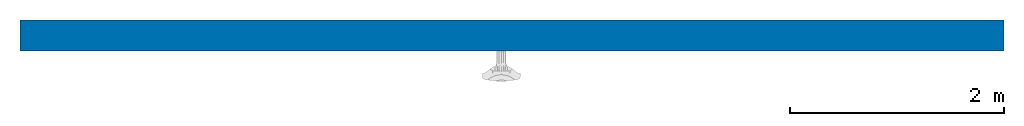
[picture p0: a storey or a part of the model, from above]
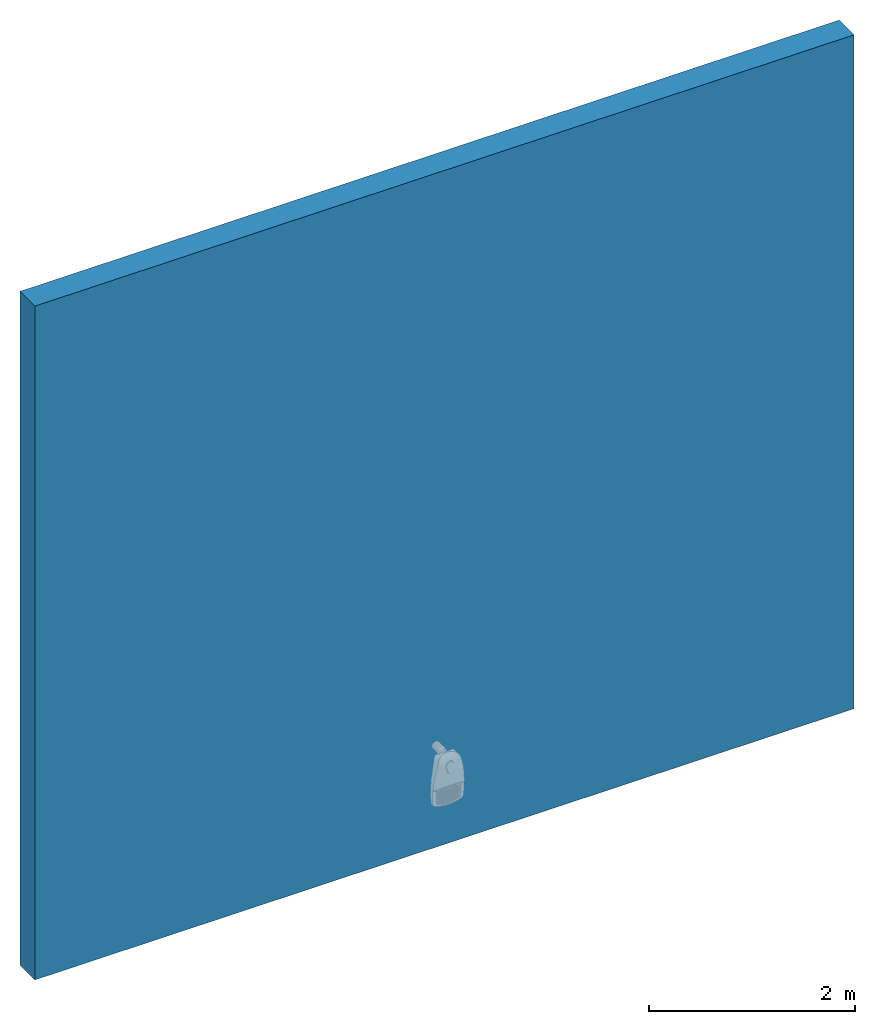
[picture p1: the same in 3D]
Properties of the parts of a building model (IFC2X3)

# File
Description: ViewDefinition [CoordinationView_V2.0]
File name: Project Number
Time: 2022-02-11T11:51:53
Written by: The EXPRESS Data Manager Version 5.02.0100.07 : 28 Aug 2013
Made in: 20160225_1515(x64) - Exporter 17.0.416.0 - Alternate UI 17.12.14.0
Comment: STEP Physical File produced by: The EXPRESS Data Manager Version 5.02.0100.07 : 28 Aug 2013 * Module: EDMstepFileFactory/EDMstandAlone * Creation date: Fri Feb 11 11:51:53 2022 * Host: JHLAP22DELL * Database: C:\Users\JoshHill\AppData\Local\Temp\{A4B69F29-368F-4F17-81F1-E311456167E6}\ifc * Database version: 5507 * Database creation date: Fri Feb 11 11:51:52 2022 * Schema: IFC2X3 * Model: DataRepository.ifc * Model creation date: Fri Feb 11 11:51:52 2022 * Header model: DataRepository.ifc_HeaderModel * Header model creation date: Fri Feb 11 11:51:52 2022 * EDMuser: sdai-user * EDMgroup: sdai-group * License ID and type: 5605 : Permanent license. Expiry date: * EDMstepFileFactory options: 020000

# IfcProject, Project Number
LongName: Project Name; Phase: Project Status

# IfcSite, Default
RefLatitude: 51, 30, 23, 112487; RefLongitude: 0, -7, -37, -956022; RefElevation: 0 mm

# IfcBuilding
Pset_BuildingCommon - NumberOfStoreys: 1

# IfcBuildingStorey, Level 0
LongName: Level 0; Elevation: 0 mm

# IfcFlowTerminal: DW Windsor KIRIUM PRO 1 (Post Top 76), DW Windsor Kirium Pro 1 (Post Top 76):DW Windsor KIRIUM PRO 1 (Post Top 76):312938
In: Level 0
Type - Material: RAL 7035 Light grey
Pset_ManufacturerTypeInformation - Manufacturer: DW Windsor Ltd
Pset_DistributionFlowElementCommon - Reference: DW Windsor KIRIUM PRO 1 (Post Top 76)

# IfcWallStandardCase: Basic Wall:Wall-Ext_102Bwk-75Ins-100LBlk-12P, Basic Wall:Wall-Ext_102Bwk-75Ins-100LBlk-12P:303882
In: Level 0
Type - PredefinedType: STANDARD; Material: Brick, Common 102.5 mm, Fiberglass Batt 75 mm, Concrete Masonry Units _Low Density 100 mm, Plaster 12.5 mm
Pset_WallCommon - Reference: Wall-Ext_102Bwk-75Ins-100LBlk-12P; LoadBearing: no; ExtendToStructure: no; IsExternal: yes; ThermalTransmittance: 0.235926 kg/K/s3
